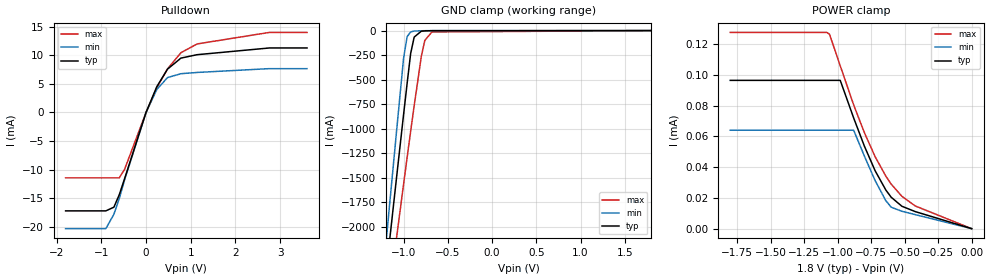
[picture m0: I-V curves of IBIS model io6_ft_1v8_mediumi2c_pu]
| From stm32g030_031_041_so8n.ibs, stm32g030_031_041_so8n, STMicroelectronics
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[Model]  io6_ft_1v8_mediumi2c_pu
Model_type I/O_open_drain
Polarity   Non-Inverting
Enable   Active-Low
Vinl =   0.540000V
Vinh =   1.260000V
Vmeas =  0.900000V
Cref =   40.000000pF
Rref =   100.000000M
Vref =   0.0V
C_comp   1.277600pF   1.236700pF   1.315100pF
[Temperature Range]   25.000000   -40.000000   0.125000k
[Pullup Reference]   1.800000V   1.600000V   2.000000V
[Pulldown Reference]   0.0V   0.0V   0.0V
[POWER Clamp Reference]   1.800000V   1.600000V   2.000000V
[GND Clamp Reference]   0.0V   0.0V   0.0V
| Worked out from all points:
|   slope of the pulldown table from 0 to 0.27 V, typ, clamps not added: 54.7 ohm
|   GND clamp passes 1 mA (typ) near -0.66 V on its own axis
[Pulldown]
|Voltage   I(typ)   I(min)   I(max)
-1.8V     -17.22mA   -20.33mA   -11.45mA
-900mV    -17.22mA   -20.33mA   -11.45mA
-720mV    -16.58mA   -17.82mA   -11.45mA
-600mV    -14.41mA   -15.08mA   -11.45mA
-480mV    -11.58mA   -11.79mA   -9.954mA
0V        0A         0A         0A
240mV     4.49mA     3.999mA    4.291mA
480mV     7.563mA    6.085mA    7.612mA
780mV     9.487mA    6.76mA     10.43mA
1.14V     10.08mA    6.976mA    11.96mA
2.76V     11.26mA    7.647mA    13.98mA
3.6V      11.26mA    7.647mA    13.98mA
[GND_clamp]
|Voltage   I(typ)   I(min)   I(max)
-1.8V     -7.471A    -7.973A    -7.298A
-1.2V     -2.489A    -2.18A     -2.954A
-1.16V    -2.16A     -1.797A    -2.674A
-1.08V    -1.505A    -1.034A    -2.118A
-1V       -857.9mA   -283.1mA   -1.568A
-960mV    -540.4mA   -62.14mA   -1.296A
-920mV    -234.4mA   -13.75mA   -1.028A
-880mV    -66.29mA   -4.855mA   -765.3mA
-800mV    -6.505mA   -2.056mA   -266mA
-760mV    -3.074mA   -1.45mA    -100.4mA
-680mV    -1.215mA   -557.1uA   -14.19mA
1.8V      0A         0A         0A
[POWER_clamp]
|Voltage   I(typ)   I(min)   I(max)
-1.8V     96.34uA    63.94uA    127.5uA
-1.08V    96.34uA    63.94uA    127.5uA
-1.06V    96.34uA    63.94uA    126.3uA
-980mV    96.34uA    63.94uA    105.8uA
-880mV    71.93uA    63.94uA    80.41uA
-800mV    53.62uA    47.15uA    62.36uA
-720mV    37.64uA    31.24uA    46.77uA
-640mV    25.08uA    18.16uA    34.09uA
-600mV    20.4uA     13.93uA    28.92uA
-520mV    14.54uA    11.31uA    20.97uA
-420mV    11.06uA    9.102uA    14.71uA
0V        0A         0A         0A
[Ramp]
| variable   typ   min   max
dV/dt_r  0.306/17.48501n   0.210/17.52538n   0.369/19.65364n
dV/dt_f  0.30492/17.70800n   0.20814/19.72167n   0.36888/17.43750n
R_load = 50.000000
